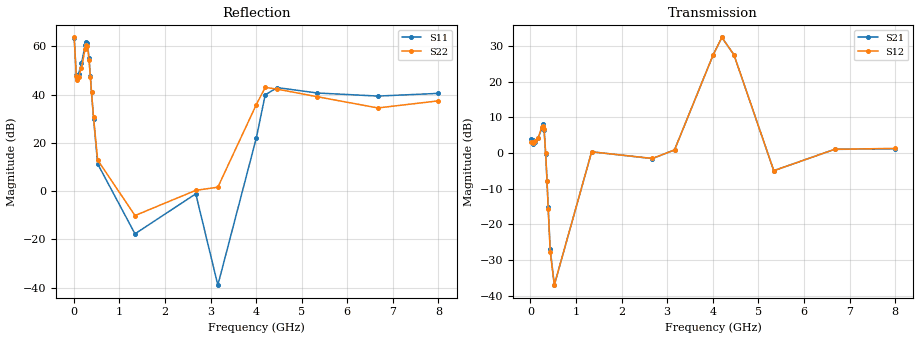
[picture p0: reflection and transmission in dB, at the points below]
!Agilent Technologies,N5230A,US43500312,A.07.50.67
!Agilent N5230A: A.07.50.67
!Date: Tuesday, June 09, 2015 15:41:19
!Correction: S11(Full 2 Port(1,2))
!S21(Full 2 Port(1,2))
!S12(Full 2 Port(1,2))
!S22(Full 2 Port(1,2))
!S2P File: Measurements: S11, S21, S12, S22:
# Hz S  MA  R 50
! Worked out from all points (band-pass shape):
!   1601 points, 10 MHz to 8 GHz, reference 50 ohm
!   highest |S21| = 32.34 dB at 4.2 GHz (marker M1); lowest = -37.0 dB at 524.4 MHz (marker M2)
!   |S21| within 3 dB of the highest: 4.053 GHz to 4.372 GHz (318.5 MHz wide, 7.56 % of centre)
!   lowest |S11| = -38.9 dB at 3.161 GHz (marker M3), VSWR 1.02, Z = 50.2 - j1.13 ohm
!   |S11| at or under -10 dB: 1.018 GHz to 1.891 GHz (872.9 MHz wide, 60 % of centre); 2.194 GHz to 2.378 GHz (184.6 MHz wide, 8.08 % of centre); 3.099 GHz to 3.213 GHz (114.3 MHz wide, 3.62 % of centre)
!   |S22| runs from -16.2 to 63.6 dB; largest |S21 - S12| = 0.56
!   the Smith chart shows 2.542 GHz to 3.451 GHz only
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1e7  1488 171.1  1.56 13.5  1.408 34.5  1521 -19.4
5.494375e7  258.1 328.0  1.51 9.2  1.44 10.2  246 94.1
6.493125e7  218.2 340.0  1.322 4.9  1.399 4.0  201.2 98.4
1.048812e8  270 378.3  1.437 7.3  1.45 6.7  230.6 116.6
1.698e8  439.5 417.1  1.598 16.8  1.637 15.3  354.8 135.7
2.497e8  1047 416.7  2.226 13.5  2.282 13.1  877.5 129.6
2.796625e8  1250 431.3  2.566 29.5  2.414 26.8  1076 144.5
2.996375e8  1167 440.9  2.111 45.8  2.167 45.1  1025 155.2
3.345938e8  576.1 476.1  0.9604 88.8  0.9985 83.3  526.8 193.1
3.645562e8  237.3 487.4  0.4 101.8  0.4088 98.3  225.7 208.8
3.89525e8  113.5 495.8  0.1749 112.0  0.1658 109.2  111.6 221.8
4.344688e8  31.84 506.2  0.04484 114.8  0.0415 114.2  33.54 243.7
5.243562e8  3.677 538.0  0.01409 138.0  0.01424 135.3  4.417 309.9
1.343331e9  0.1309 839.3  1.037 190.3  1.037 190.3  0.3128 795.7
2.676662e9  0.8809 717.9  0.8333 190.0  0.8367 190.1  1.04 1246.2
3.161056e9  0.01137 639.4  1.101 220.3  1.103 220.4  1.208 1369.0
4.005e9  12.63 591.8  23.29 263.7  23.33 264.0  61.95 1535.2
4.199756e9  98.39 384.5  41.38 178.6  41.51 179.0  140.2 1491.6
4.464425e9  139 306.9  23.64 87.7  23.73 87.9  129.2 1445.3
5.338331e9  107.6 304.3  0.5646 -4.9  0.5639 -4.9  90.04 1421.0
6.671662e9  92.79 318.8  1.122 30.9  1.123 30.8  52.75 1365.5
8e9  105.6 329.1  1.141 19.6  1.159 19.3  73.93 1323.1
